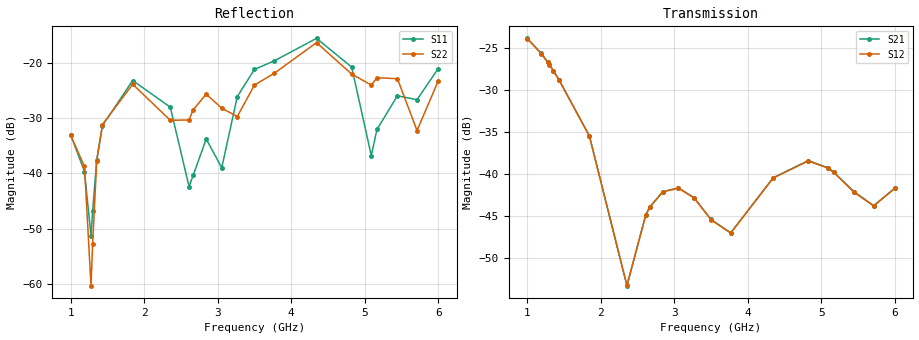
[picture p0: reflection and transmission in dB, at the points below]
!Agilent Technologies,E8364B,MY43040528,A.07.50.67
!Agilent E8364B: A.07.50.67
!Date: Sunday, March 01, 2026 16:55:14
!Correction: S11(Full 2 Port(1,2))
!S21(Full 2 Port(1,2))
!S12(Full 2 Port(1,2))
!S22(Full 2 Port(1,2))
!S2P File: Measurements: S11, S21, S12, S22:
# Hz S  dB  R 50
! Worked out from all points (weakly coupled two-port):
!   451 points, 1 GHz to 6 GHz, reference 50 ohm
!   highest |S21| = -23.82 dB at 1 GHz (marker M1); lowest = -53.3 dB at 2.356 GHz (marker M2)
!   lowest |S11| = -51.2 dB at 1.278 GHz (marker M3), VSWR 1.01, Z = 50.1 - j0.266 ohm
!   |S11| at or under -10 dB: start of sweep to end of sweep
!   |S22| runs from -64.3 to -16.3 dB; largest |S21 - S12| = 0.00028
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1e9  -32.99 27.0  -23.82 152.7  -23.85 152.8  -33.13 -2.7
1.188889e9  -39.67 16.3  -25.59 44.9  -25.63 44.9  -38.74 -9.9
1.277778e9  -51.22 -75.0  -26.63 -5.4  -26.67 -5.4  -60.27 -42.7
1.3e9  -46.79 -127.1  -26.92 -17.9  -26.95 -17.8  -52.71 137.4
1.355556e9  -37.58 -164.4  -27.66 -48.9  -27.70 -48.8  -37.76 120.8
1.433333e9  -31.37 168.5  -28.78 -91.7  -28.81 -91.7  -31.19 101.9
1.844444e9  -23.25 77.0  -35.43 48.0  -35.47 48.1  -23.92 -4.9
2.355556e9  -28.05 1.4  -53.30 -149.4  -53.25 -149.3  -30.42 -80.8
2.611111e9  -42.39 14.9  -44.88 132.4  -44.93 132.4  -30.37 -54.1
2.666667e9  -40.36 54.4  -43.90 104.4  -43.93 104.6  -28.53 -57.8
2.844444e9  -33.80 52.0  -42.08 11.8  -42.12 11.8  -25.71 -91.4
3.055556e9  -38.99 81.1  -41.65 -100.5  -41.68 -100.6  -28.24 -129.3
3.266667e9  -26.15 100.9  -42.79 148.8  -42.83 148.9  -29.75 -108.2
3.5e9  -21.24 62.4  -45.41 37.1  -45.45 37.2  -24.07 -130.1
3.766667e9  -19.72 33.5  -47.00 -66.1  -47.03 -66.1  -21.97 -157.5
4.344444e9  -15.64 -41.4  -40.43 22.5  -40.47 22.6  -16.41 111.7
4.822222e9  -20.82 -122.2  -38.38 114.4  -38.43 114.5  -22.08 34.4
5.088889e9  -36.78 -102.5  -39.25 -43.4  -39.29 -43.4  -24.07 41.1
5.166667e9  -32.06 -56.4  -39.75 -90.4  -39.80 -90.4  -22.75 34.2
5.444444e9  -26.01 -82.4  -42.11 93.4  -42.16 93.5  -22.92 -19.4
5.711111e9  -26.70 -66.2  -43.75 -95.6  -43.80 -95.7  -32.28 -16.1
6e9  -21.08 -79.4  -41.66 59.9  -41.69 59.9  -23.30 -16.1
